VERSION 5.7 ;
  NOWIREEXTENSIONATPIN ON ;
  DIVIDERCHAR "/" ;
  BUSBITCHARS "[]" ;
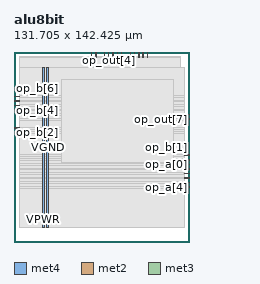
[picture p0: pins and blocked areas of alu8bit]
MACRO alu8bit
  CLASS BLOCK ;
  FOREIGN alu8bit ;
  ORIGIN 0.000 0.000 ;
  SIZE 131.705 BY 142.425 ;
  PIN VGND
    DIRECTION INOUT ;
    USE GROUND ;
    PORT
      LAYER met4 ;
        RECT 24.340 10.640 25.940 130.800 ;
    END
  END VGND
  PIN VPWR
    DIRECTION INOUT ;
    USE POWER ;
    PORT
      LAYER met4 ;
        RECT 21.040 10.640 22.640 130.800 ;
    END
  END VPWR
  PIN inst[0]
    DIRECTION INPUT ;
    USE SIGNAL ;
    ANTENNAGATEAREA 0.126000 ;
    PORT
      LAYER met2 ;
        RECT 96.690 138.425 96.970 142.425 ;
    END
  END inst[0]
  PIN inst[1]
    DIRECTION INPUT ;
    USE SIGNAL ;
    ANTENNAGATEAREA 0.196500 ;
    PORT
      LAYER met2 ;
        RECT 93.470 138.425 93.750 142.425 ;
    END
  END inst[1]
  PIN inst[2]
    DIRECTION INPUT ;
    USE SIGNAL ;
    ANTENNAGATEAREA 0.213000 ;
    PORT
      LAYER met2 ;
        RECT 99.910 138.425 100.190 142.425 ;
    END
  END inst[2]
  PIN inst[3]
    DIRECTION INPUT ;
    USE SIGNAL ;
    ANTENNAGATEAREA 0.196500 ;
    PORT
      LAYER met2 ;
        RECT 90.250 138.425 90.530 142.425 ;
    END
  END inst[3]
  PIN op_a[0]
    DIRECTION INPUT ;
    USE SIGNAL ;
    ANTENNAGATEAREA 0.196500 ;
    PORT
      LAYER met3 ;
        RECT 127.705 57.840 131.705 58.440 ;
    END
  END op_a[0]
  PIN op_a[1]
    DIRECTION INPUT ;
    USE SIGNAL ;
    ANTENNAGATEAREA 0.196500 ;
    PORT
      LAYER met3 ;
        RECT 127.705 54.440 131.705 55.040 ;
    END
  END op_a[1]
  PIN op_a[2]
    DIRECTION INPUT ;
    USE SIGNAL ;
    ANTENNAGATEAREA 0.126000 ;
    PORT
      LAYER met3 ;
        RECT 127.705 61.240 131.705 61.840 ;
    END
  END op_a[2]
  PIN op_a[3]
    DIRECTION INPUT ;
    USE SIGNAL ;
    ANTENNAGATEAREA 0.196500 ;
    PORT
      LAYER met3 ;
        RECT 127.705 47.640 131.705 48.240 ;
    END
  END op_a[3]
  PIN op_a[4]
    DIRECTION INPUT ;
    USE SIGNAL ;
    ANTENNAGATEAREA 0.196500 ;
    PORT
      LAYER met3 ;
        RECT 127.705 40.840 131.705 41.440 ;
    END
  END op_a[4]
  PIN op_a[5]
    DIRECTION INPUT ;
    USE SIGNAL ;
    ANTENNAGATEAREA 0.213000 ;
    PORT
      LAYER met3 ;
        RECT 127.705 44.240 131.705 44.840 ;
    END
  END op_a[5]
  PIN op_a[6]
    DIRECTION INPUT ;
    USE SIGNAL ;
    ANTENNAGATEAREA 0.196500 ;
    PORT
      LAYER met2 ;
        RECT 74.150 138.425 74.430 142.425 ;
    END
  END op_a[6]
  PIN op_a[7]
    DIRECTION INPUT ;
    USE SIGNAL ;
    ANTENNAGATEAREA 0.213000 ;
    PORT
      LAYER met2 ;
        RECT 80.590 138.425 80.870 142.425 ;
    END
  END op_a[7]
  PIN op_b[0]
    DIRECTION INPUT ;
    USE SIGNAL ;
    ANTENNAGATEAREA 0.495000 ;
    PORT
      LAYER met3 ;
        RECT 127.705 51.040 131.705 51.640 ;
    END
  END op_b[0]
  PIN op_b[1]
    DIRECTION INPUT ;
    USE SIGNAL ;
    ANTENNAGATEAREA 0.196500 ;
    PORT
      LAYER met3 ;
        RECT 127.705 64.640 131.705 65.240 ;
    END
  END op_b[1]
  PIN op_b[2]
    DIRECTION INPUT ;
    USE SIGNAL ;
    ANTENNAGATEAREA 0.196500 ;
    PORT
      LAYER met3 ;
        RECT 0.000 81.640 4.000 82.240 ;
    END
  END op_b[2]
  PIN op_b[3]
    DIRECTION INPUT ;
    USE SIGNAL ;
    ANTENNAGATEAREA 0.196500 ;
    PORT
      LAYER met3 ;
        RECT 0.000 85.040 4.000 85.640 ;
    END
  END op_b[3]
  PIN op_b[4]
    DIRECTION INPUT ;
    USE SIGNAL ;
    ANTENNAGATEAREA 0.742500 ;
    PORT
      LAYER met3 ;
        RECT 0.000 98.640 4.000 99.240 ;
    END
  END op_b[4]
  PIN op_b[5]
    DIRECTION INPUT ;
    USE SIGNAL ;
    ANTENNAGATEAREA 0.213000 ;
    PORT
      LAYER met3 ;
        RECT 0.000 105.440 4.000 106.040 ;
    END
  END op_b[5]
  PIN op_b[6]
    DIRECTION INPUT ;
    USE SIGNAL ;
    ANTENNAGATEAREA 0.196500 ;
    PORT
      LAYER met3 ;
        RECT 0.000 108.840 4.000 109.440 ;
    END
  END op_b[6]
  PIN op_b[7]
    DIRECTION INPUT ;
    USE SIGNAL ;
    ANTENNAGATEAREA 0.196500 ;
    PORT
      LAYER met3 ;
        RECT 0.000 102.040 4.000 102.640 ;
    END
  END op_b[7]
  PIN op_out[0]
    DIRECTION OUTPUT ;
    USE SIGNAL ;
    ANTENNADIFFAREA 1.782000 ;
    PORT
      LAYER met2 ;
        RECT 87.030 138.425 87.310 142.425 ;
    END
  END op_out[0]
  PIN op_out[1]
    DIRECTION OUTPUT ;
    USE SIGNAL ;
    ANTENNADIFFAREA 1.782000 ;
    PORT
      LAYER met2 ;
        RECT 61.270 138.425 61.550 142.425 ;
    END
  END op_out[1]
  PIN op_out[2]
    DIRECTION OUTPUT ;
    USE SIGNAL ;
    ANTENNADIFFAREA 1.336500 ;
    PORT
      LAYER met2 ;
        RECT 58.050 138.425 58.330 142.425 ;
    END
  END op_out[2]
  PIN op_out[3]
    DIRECTION OUTPUT ;
    USE SIGNAL ;
    ANTENNADIFFAREA 0.445500 ;
    PORT
      LAYER met2 ;
        RECT 67.710 138.425 67.990 142.425 ;
    END
  END op_out[3]
  PIN op_out[4]
    DIRECTION OUTPUT ;
    USE SIGNAL ;
    ANTENNADIFFAREA 0.891000 ;
    PORT
      LAYER met2 ;
        RECT 70.930 138.425 71.210 142.425 ;
    END
  END op_out[4]
  PIN op_out[5]
    DIRECTION OUTPUT ;
    USE SIGNAL ;
    ANTENNADIFFAREA 0.891000 ;
    PORT
      LAYER met2 ;
        RECT 77.370 138.425 77.650 142.425 ;
    END
  END op_out[5]
  PIN op_out[6]
    DIRECTION OUTPUT ;
    USE SIGNAL ;
    ANTENNADIFFAREA 1.336500 ;
    PORT
      LAYER met3 ;
        RECT 127.705 95.240 131.705 95.840 ;
    END
  END op_out[6]
  PIN op_out[7]
    DIRECTION OUTPUT ;
    USE SIGNAL ;
    ANTENNADIFFAREA 1.336500 ;
    PORT
      LAYER met3 ;
        RECT 127.705 91.840 131.705 92.440 ;
    END
  END op_out[7]
  OBS
      LAYER nwell ;
        RECT 5.330 10.795 126.230 130.645 ;
      LAYER li1 ;
        RECT 5.520 10.795 126.040 130.645 ;
      LAYER met1 ;
        RECT 4.210 10.640 126.040 130.800 ;
      LAYER met2 ;
        RECT 4.230 138.145 57.770 139.130 ;
        RECT 58.610 138.145 60.990 139.130 ;
        RECT 61.830 138.145 67.430 139.130 ;
        RECT 68.270 138.145 70.650 139.130 ;
        RECT 71.490 138.145 73.870 139.130 ;
        RECT 74.710 138.145 77.090 139.130 ;
        RECT 77.930 138.145 80.310 139.130 ;
        RECT 81.150 138.145 86.750 139.130 ;
        RECT 87.590 138.145 89.970 139.130 ;
        RECT 90.810 138.145 93.190 139.130 ;
        RECT 94.030 138.145 96.410 139.130 ;
        RECT 97.250 138.145 99.630 139.130 ;
        RECT 100.470 138.145 124.570 139.130 ;
        RECT 4.230 10.695 124.570 138.145 ;
      LAYER met3 ;
        RECT 3.990 109.840 127.705 130.725 ;
        RECT 4.400 108.440 127.705 109.840 ;
        RECT 3.990 106.440 127.705 108.440 ;
        RECT 4.400 105.040 127.705 106.440 ;
        RECT 3.990 103.040 127.705 105.040 ;
        RECT 4.400 101.640 127.705 103.040 ;
        RECT 3.990 99.640 127.705 101.640 ;
        RECT 4.400 98.240 127.705 99.640 ;
        RECT 3.990 96.240 127.705 98.240 ;
        RECT 3.990 94.840 127.305 96.240 ;
        RECT 3.990 92.840 127.705 94.840 ;
        RECT 3.990 91.440 127.305 92.840 ;
        RECT 3.990 86.040 127.705 91.440 ;
        RECT 4.400 84.640 127.705 86.040 ;
        RECT 3.990 82.640 127.705 84.640 ;
        RECT 4.400 81.240 127.705 82.640 ;
        RECT 3.990 65.640 127.705 81.240 ;
        RECT 3.990 64.240 127.305 65.640 ;
        RECT 3.990 62.240 127.705 64.240 ;
        RECT 3.990 60.840 127.305 62.240 ;
        RECT 3.990 58.840 127.705 60.840 ;
        RECT 3.990 57.440 127.305 58.840 ;
        RECT 3.990 55.440 127.705 57.440 ;
        RECT 3.990 54.040 127.305 55.440 ;
        RECT 3.990 52.040 127.705 54.040 ;
        RECT 3.990 50.640 127.305 52.040 ;
        RECT 3.990 48.640 127.705 50.640 ;
        RECT 3.990 47.240 127.305 48.640 ;
        RECT 3.990 45.240 127.705 47.240 ;
        RECT 3.990 43.840 127.305 45.240 ;
        RECT 3.990 41.840 127.705 43.840 ;
        RECT 3.990 40.440 127.305 41.840 ;
        RECT 3.990 10.715 127.705 40.440 ;
      LAYER met4 ;
        RECT 35.255 59.335 119.305 121.545 ;
  END
END alu8bit
END LIBRARY

